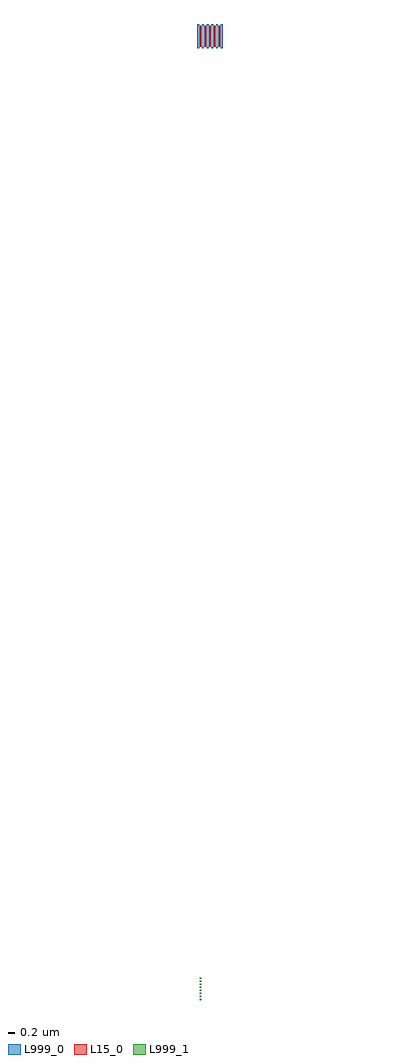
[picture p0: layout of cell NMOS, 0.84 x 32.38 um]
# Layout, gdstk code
import gdstk
lib = gdstk.Library(unit=1e-6, precision=1e-09)
def R(c, l, rs):  # rectangles x0, y0, x1, y1
    for r in rs: c.add(gdstk.rectangle(r[:2], r[2:], *l))
def A(c, l, x, y, w, h, nx, ny, dx, dy):  # array of equal rectangles
    R(c, l, [(x+i*dx, y+j*dy, x+i*dx+w, y+j*dy+h) for i in range(nx) for j in range(ny)])
L15_0 = (15, 0)
L999_0 = (999, 0)
L999_1 = (999, 1)

nmos = lib.new_cell('NMOS')
A(nmos, L15_0, -0.337, -0.35, 0.05, 0.7, 5, 1, 0.156, 0)
A(nmos, L999_0, -0.42, -0.406, 0.06, 0.812, 6, 1, 0.156, 0)
R(nmos, L999_0, [(-0.34,-0.35,0.34,0.35)])
A(nmos, L999_1, -0.332, -31.97, 0.04, 0.04, 1, 8, 0, 0.1)

lib.write_gds('NMOS.gds')
